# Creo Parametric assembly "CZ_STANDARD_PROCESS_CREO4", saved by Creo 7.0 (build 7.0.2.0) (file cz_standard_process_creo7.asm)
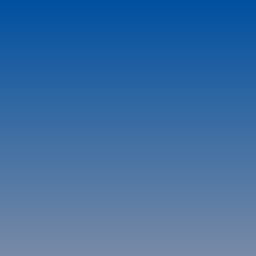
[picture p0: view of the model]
Units: Asm Proc; MM, KILOGRAM, HOURS

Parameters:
  ERSTELLUNGSDATUM = "."
  BEARBEITER = "."
  KONSTRUKTIONSGRUPPE = "."
  ZEICHNUNGSNUMMER = "000000-0000-000/01"
  TEILDOKUMENT = "001"
  VERSION = "01"
  MATERIALNUMMER = "000000-0000-000"
  KOMP_STUFE = "G"
  KOMP_CHAR = "M"
  BENENNUNG = "MAW XXXXX"

Other parameters: PREIS

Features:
  1. datum plane "A_Y-Z"
  2. datum plane "A_X-Z"
  3. datum plane "A_X-Y"
  4. coordinate system
  5. datum axis
  6. datum axis
  7. datum axis

Other named items: A_X_ACHSE, A_Z_ACHSE, A_Y_ACHSE, X0Y0Z0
